VERSION 5.7 ;
BUSBITCHARS "[]" ;
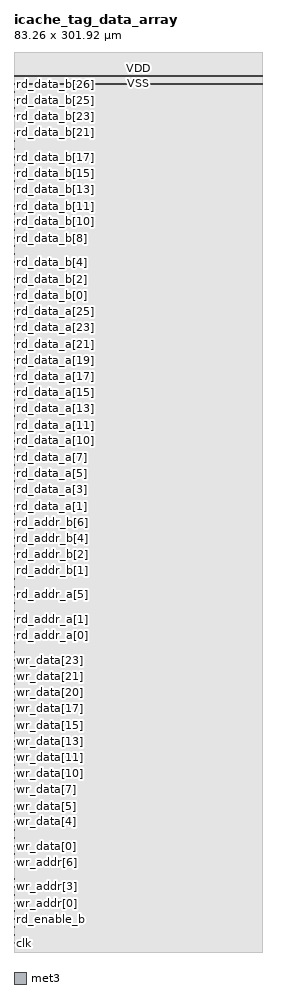
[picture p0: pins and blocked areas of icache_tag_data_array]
MACRO icache_tag_data_array
  FOREIGN icache_tag_data_array 0 0 ;
  SYMMETRY X Y R90 ;
  SIZE 83.260 BY 301.920 ;
  CLASS BLOCK ;
  PIN clk
    DIRECTION INPUT ;
    USE SIGNAL ;
    SHAPE ABUTMENT ;
    PORT
      LAYER met3 ;
      RECT 0.000 2.720 0.300 3.020 ;
    END
  END clk
  PIN wr_enable
    DIRECTION INPUT ;
    USE SIGNAL ;
    SHAPE ABUTMENT ;
    PORT
      LAYER met3 ;
      RECT 0.000 5.440 0.300 5.740 ;
    END
  END wr_enable
  PIN rd_enable_a
    DIRECTION INPUT ;
    USE SIGNAL ;
    SHAPE ABUTMENT ;
    PORT
      LAYER met3 ;
      RECT 0.000 8.160 0.300 8.460 ;
    END
  END rd_enable_a
  PIN rd_enable_b
    DIRECTION INPUT ;
    USE SIGNAL ;
    SHAPE ABUTMENT ;
    PORT
      LAYER met3 ;
      RECT 0.000 10.880 0.300 11.180 ;
    END
  END rd_enable_b
  PIN wr_addr[0]
    DIRECTION INPUT ;
    USE SIGNAL ;
    SHAPE ABUTMENT ;
    PORT
      LAYER met3 ;
      RECT 0.000 13.600 0.300 13.900 ;
    END
  END wr_addr[0]
  PIN wr_addr[1]
    DIRECTION INPUT ;
    USE SIGNAL ;
    SHAPE ABUTMENT ;
    PORT
      LAYER met3 ;
      RECT 0.000 16.320 0.300 16.620 ;
    END
  END wr_addr[1]
  PIN wr_addr[2]
    DIRECTION INPUT ;
    USE SIGNAL ;
    SHAPE ABUTMENT ;
    PORT
      LAYER met3 ;
      RECT 0.000 19.040 0.300 19.340 ;
    END
  END wr_addr[2]
  PIN wr_addr[3]
    DIRECTION INPUT ;
    USE SIGNAL ;
    SHAPE ABUTMENT ;
    PORT
      LAYER met3 ;
      RECT 0.000 21.760 0.300 22.060 ;
    END
  END wr_addr[3]
  PIN wr_addr[4]
    DIRECTION INPUT ;
    USE SIGNAL ;
    SHAPE ABUTMENT ;
    PORT
      LAYER met3 ;
      RECT 0.000 24.480 0.300 24.780 ;
    END
  END wr_addr[4]
  PIN wr_addr[5]
    DIRECTION INPUT ;
    USE SIGNAL ;
    SHAPE ABUTMENT ;
    PORT
      LAYER met3 ;
      RECT 0.000 27.200 0.300 27.500 ;
    END
  END wr_addr[5]
  PIN wr_addr[6]
    DIRECTION INPUT ;
    USE SIGNAL ;
    SHAPE ABUTMENT ;
    PORT
      LAYER met3 ;
      RECT 0.000 29.920 0.300 30.220 ;
    END
  END wr_addr[6]
  PIN wr_data[0]
    DIRECTION INPUT ;
    USE SIGNAL ;
    SHAPE ABUTMENT ;
    PORT
      LAYER met3 ;
      RECT 0.000 32.640 0.300 32.940 ;
    END
  END wr_data[0]
  PIN wr_data[1]
    DIRECTION INPUT ;
    USE SIGNAL ;
    SHAPE ABUTMENT ;
    PORT
      LAYER met3 ;
      RECT 0.000 35.360 0.300 35.660 ;
    END
  END wr_data[1]
  PIN wr_data[2]
    DIRECTION INPUT ;
    USE SIGNAL ;
    SHAPE ABUTMENT ;
    PORT
      LAYER met3 ;
      RECT 0.000 38.080 0.300 38.380 ;
    END
  END wr_data[2]
  PIN wr_data[3]
    DIRECTION INPUT ;
    USE SIGNAL ;
    SHAPE ABUTMENT ;
    PORT
      LAYER met3 ;
      RECT 0.000 40.800 0.300 41.100 ;
    END
  END wr_data[3]
  PIN wr_data[4]
    DIRECTION INPUT ;
    USE SIGNAL ;
    SHAPE ABUTMENT ;
    PORT
      LAYER met3 ;
      RECT 0.000 43.520 0.300 43.820 ;
    END
  END wr_data[4]
  PIN wr_data[5]
    DIRECTION INPUT ;
    USE SIGNAL ;
    SHAPE ABUTMENT ;
    PORT
      LAYER met3 ;
      RECT 0.000 46.240 0.300 46.540 ;
    END
  END wr_data[5]
  PIN wr_data[6]
    DIRECTION INPUT ;
    USE SIGNAL ;
    SHAPE ABUTMENT ;
    PORT
      LAYER met3 ;
      RECT 0.000 48.960 0.300 49.260 ;
    END
  END wr_data[6]
  PIN wr_data[7]
    DIRECTION INPUT ;
    USE SIGNAL ;
    SHAPE ABUTMENT ;
    PORT
      LAYER met3 ;
      RECT 0.000 51.680 0.300 51.980 ;
    END
  END wr_data[7]
  PIN wr_data[8]
    DIRECTION INPUT ;
    USE SIGNAL ;
    SHAPE ABUTMENT ;
    PORT
      LAYER met3 ;
      RECT 0.000 54.400 0.300 54.700 ;
    END
  END wr_data[8]
  PIN wr_data[9]
    DIRECTION INPUT ;
    USE SIGNAL ;
    SHAPE ABUTMENT ;
    PORT
      LAYER met3 ;
      RECT 0.000 57.120 0.300 57.420 ;
    END
  END wr_data[9]
  PIN wr_data[10]
    DIRECTION INPUT ;
    USE SIGNAL ;
    SHAPE ABUTMENT ;
    PORT
      LAYER met3 ;
      RECT 0.000 59.840 0.300 60.140 ;
    END
  END wr_data[10]
  PIN wr_data[11]
    DIRECTION INPUT ;
    USE SIGNAL ;
    SHAPE ABUTMENT ;
    PORT
      LAYER met3 ;
      RECT 0.000 62.560 0.300 62.860 ;
    END
  END wr_data[11]
  PIN wr_data[12]
    DIRECTION INPUT ;
    USE SIGNAL ;
    SHAPE ABUTMENT ;
    PORT
      LAYER met3 ;
      RECT 0.000 65.280 0.300 65.580 ;
    END
  END wr_data[12]
  PIN wr_data[13]
    DIRECTION INPUT ;
    USE SIGNAL ;
    SHAPE ABUTMENT ;
    PORT
      LAYER met3 ;
      RECT 0.000 68.000 0.300 68.300 ;
    END
  END wr_data[13]
  PIN wr_data[14]
    DIRECTION INPUT ;
    USE SIGNAL ;
    SHAPE ABUTMENT ;
    PORT
      LAYER met3 ;
      RECT 0.000 70.720 0.300 71.020 ;
    END
  END wr_data[14]
  PIN wr_data[15]
    DIRECTION INPUT ;
    USE SIGNAL ;
    SHAPE ABUTMENT ;
    PORT
      LAYER met3 ;
      RECT 0.000 73.440 0.300 73.740 ;
    END
  END wr_data[15]
  PIN wr_data[16]
    DIRECTION INPUT ;
    USE SIGNAL ;
    SHAPE ABUTMENT ;
    PORT
      LAYER met3 ;
      RECT 0.000 76.160 0.300 76.460 ;
    END
  END wr_data[16]
  PIN wr_data[17]
    DIRECTION INPUT ;
    USE SIGNAL ;
    SHAPE ABUTMENT ;
    PORT
      LAYER met3 ;
      RECT 0.000 78.880 0.300 79.180 ;
    END
  END wr_data[17]
  PIN wr_data[18]
    DIRECTION INPUT ;
    USE SIGNAL ;
    SHAPE ABUTMENT ;
    PORT
      LAYER met3 ;
      RECT 0.000 81.600 0.300 81.900 ;
    END
  END wr_data[18]
  PIN wr_data[19]
    DIRECTION INPUT ;
    USE SIGNAL ;
    SHAPE ABUTMENT ;
    PORT
      LAYER met3 ;
      RECT 0.000 84.320 0.300 84.620 ;
    END
  END wr_data[19]
  PIN wr_data[20]
    DIRECTION INPUT ;
    USE SIGNAL ;
    SHAPE ABUTMENT ;
    PORT
      LAYER met3 ;
      RECT 0.000 87.040 0.300 87.340 ;
    END
  END wr_data[20]
  PIN wr_data[21]
    DIRECTION INPUT ;
    USE SIGNAL ;
    SHAPE ABUTMENT ;
    PORT
      LAYER met3 ;
      RECT 0.000 89.760 0.300 90.060 ;
    END
  END wr_data[21]
  PIN wr_data[22]
    DIRECTION INPUT ;
    USE SIGNAL ;
    SHAPE ABUTMENT ;
    PORT
      LAYER met3 ;
      RECT 0.000 92.480 0.300 92.780 ;
    END
  END wr_data[22]
  PIN wr_data[23]
    DIRECTION INPUT ;
    USE SIGNAL ;
    SHAPE ABUTMENT ;
    PORT
      LAYER met3 ;
      RECT 0.000 95.200 0.300 95.500 ;
    END
  END wr_data[23]
  PIN wr_data[24]
    DIRECTION INPUT ;
    USE SIGNAL ;
    SHAPE ABUTMENT ;
    PORT
      LAYER met3 ;
      RECT 0.000 97.920 0.300 98.220 ;
    END
  END wr_data[24]
  PIN wr_data[25]
    DIRECTION INPUT ;
    USE SIGNAL ;
    SHAPE ABUTMENT ;
    PORT
      LAYER met3 ;
      RECT 0.000 100.640 0.300 100.940 ;
    END
  END wr_data[25]
  PIN wr_data[26]
    DIRECTION INPUT ;
    USE SIGNAL ;
    SHAPE ABUTMENT ;
    PORT
      LAYER met3 ;
      RECT 0.000 103.360 0.300 103.660 ;
    END
  END wr_data[26]
  PIN rd_addr_a[0]
    DIRECTION INPUT ;
    USE SIGNAL ;
    SHAPE ABUTMENT ;
    PORT
      LAYER met3 ;
      RECT 0.000 106.080 0.300 106.380 ;
    END
  END rd_addr_a[0]
  PIN rd_addr_a[1]
    DIRECTION INPUT ;
    USE SIGNAL ;
    SHAPE ABUTMENT ;
    PORT
      LAYER met3 ;
      RECT 0.000 108.800 0.300 109.100 ;
    END
  END rd_addr_a[1]
  PIN rd_addr_a[2]
    DIRECTION INPUT ;
    USE SIGNAL ;
    SHAPE ABUTMENT ;
    PORT
      LAYER met3 ;
      RECT 0.000 111.520 0.300 111.820 ;
    END
  END rd_addr_a[2]
  PIN rd_addr_a[3]
    DIRECTION INPUT ;
    USE SIGNAL ;
    SHAPE ABUTMENT ;
    PORT
      LAYER met3 ;
      RECT 0.000 114.240 0.300 114.540 ;
    END
  END rd_addr_a[3]
  PIN rd_addr_a[4]
    DIRECTION INPUT ;
    USE SIGNAL ;
    SHAPE ABUTMENT ;
    PORT
      LAYER met3 ;
      RECT 0.000 116.960 0.300 117.260 ;
    END
  END rd_addr_a[4]
  PIN rd_addr_a[5]
    DIRECTION INPUT ;
    USE SIGNAL ;
    SHAPE ABUTMENT ;
    PORT
      LAYER met3 ;
      RECT 0.000 119.680 0.300 119.980 ;
    END
  END rd_addr_a[5]
  PIN rd_addr_a[6]
    DIRECTION INPUT ;
    USE SIGNAL ;
    SHAPE ABUTMENT ;
    PORT
      LAYER met3 ;
      RECT 0.000 122.400 0.300 122.700 ;
    END
  END rd_addr_a[6]
  PIN rd_addr_b[0]
    DIRECTION INPUT ;
    USE SIGNAL ;
    SHAPE ABUTMENT ;
    PORT
      LAYER met3 ;
      RECT 0.000 125.120 0.300 125.420 ;
    END
  END rd_addr_b[0]
  PIN rd_addr_b[1]
    DIRECTION INPUT ;
    USE SIGNAL ;
    SHAPE ABUTMENT ;
    PORT
      LAYER met3 ;
      RECT 0.000 127.840 0.300 128.140 ;
    END
  END rd_addr_b[1]
  PIN rd_addr_b[2]
    DIRECTION INPUT ;
    USE SIGNAL ;
    SHAPE ABUTMENT ;
    PORT
      LAYER met3 ;
      RECT 0.000 130.560 0.300 130.860 ;
    END
  END rd_addr_b[2]
  PIN rd_addr_b[3]
    DIRECTION INPUT ;
    USE SIGNAL ;
    SHAPE ABUTMENT ;
    PORT
      LAYER met3 ;
      RECT 0.000 133.280 0.300 133.580 ;
    END
  END rd_addr_b[3]
  PIN rd_addr_b[4]
    DIRECTION INPUT ;
    USE SIGNAL ;
    SHAPE ABUTMENT ;
    PORT
      LAYER met3 ;
      RECT 0.000 136.000 0.300 136.300 ;
    END
  END rd_addr_b[4]
  PIN rd_addr_b[5]
    DIRECTION INPUT ;
    USE SIGNAL ;
    SHAPE ABUTMENT ;
    PORT
      LAYER met3 ;
      RECT 0.000 138.720 0.300 139.020 ;
    END
  END rd_addr_b[5]
  PIN rd_addr_b[6]
    DIRECTION INPUT ;
    USE SIGNAL ;
    SHAPE ABUTMENT ;
    PORT
      LAYER met3 ;
      RECT 0.000 141.440 0.300 141.740 ;
    END
  END rd_addr_b[6]
  PIN rd_data_a[0]
    DIRECTION OUTPUT ;
    USE SIGNAL ;
    SHAPE ABUTMENT ;
    PORT
      LAYER met3 ;
      RECT 0.000 144.160 0.300 144.460 ;
    END
  END rd_data_a[0]
  PIN rd_data_a[1]
    DIRECTION OUTPUT ;
    USE SIGNAL ;
    SHAPE ABUTMENT ;
    PORT
      LAYER met3 ;
      RECT 0.000 146.880 0.300 147.180 ;
    END
  END rd_data_a[1]
  PIN rd_data_a[2]
    DIRECTION OUTPUT ;
    USE SIGNAL ;
    SHAPE ABUTMENT ;
    PORT
      LAYER met3 ;
      RECT 0.000 149.600 0.300 149.900 ;
    END
  END rd_data_a[2]
  PIN rd_data_a[3]
    DIRECTION OUTPUT ;
    USE SIGNAL ;
    SHAPE ABUTMENT ;
    PORT
      LAYER met3 ;
      RECT 0.000 152.320 0.300 152.620 ;
    END
  END rd_data_a[3]
  PIN rd_data_a[4]
    DIRECTION OUTPUT ;
    USE SIGNAL ;
    SHAPE ABUTMENT ;
    PORT
      LAYER met3 ;
      RECT 0.000 155.040 0.300 155.340 ;
    END
  END rd_data_a[4]
  PIN rd_data_a[5]
    DIRECTION OUTPUT ;
    USE SIGNAL ;
    SHAPE ABUTMENT ;
    PORT
      LAYER met3 ;
      RECT 0.000 157.760 0.300 158.060 ;
    END
  END rd_data_a[5]
  PIN rd_data_a[6]
    DIRECTION OUTPUT ;
    USE SIGNAL ;
    SHAPE ABUTMENT ;
    PORT
      LAYER met3 ;
      RECT 0.000 160.480 0.300 160.780 ;
    END
  END rd_data_a[6]
  PIN rd_data_a[7]
    DIRECTION OUTPUT ;
    USE SIGNAL ;
    SHAPE ABUTMENT ;
    PORT
      LAYER met3 ;
      RECT 0.000 163.200 0.300 163.500 ;
    END
  END rd_data_a[7]
  PIN rd_data_a[8]
    DIRECTION OUTPUT ;
    USE SIGNAL ;
    SHAPE ABUTMENT ;
    PORT
      LAYER met3 ;
      RECT 0.000 165.920 0.300 166.220 ;
    END
  END rd_data_a[8]
  PIN rd_data_a[9]
    DIRECTION OUTPUT ;
    USE SIGNAL ;
    SHAPE ABUTMENT ;
    PORT
      LAYER met3 ;
      RECT 0.000 168.640 0.300 168.940 ;
    END
  END rd_data_a[9]
  PIN rd_data_a[10]
    DIRECTION OUTPUT ;
    USE SIGNAL ;
    SHAPE ABUTMENT ;
    PORT
      LAYER met3 ;
      RECT 0.000 171.360 0.300 171.660 ;
    END
  END rd_data_a[10]
  PIN rd_data_a[11]
    DIRECTION OUTPUT ;
    USE SIGNAL ;
    SHAPE ABUTMENT ;
    PORT
      LAYER met3 ;
      RECT 0.000 174.080 0.300 174.380 ;
    END
  END rd_data_a[11]
  PIN rd_data_a[12]
    DIRECTION OUTPUT ;
    USE SIGNAL ;
    SHAPE ABUTMENT ;
    PORT
      LAYER met3 ;
      RECT 0.000 176.800 0.300 177.100 ;
    END
  END rd_data_a[12]
  PIN rd_data_a[13]
    DIRECTION OUTPUT ;
    USE SIGNAL ;
    SHAPE ABUTMENT ;
    PORT
      LAYER met3 ;
      RECT 0.000 179.520 0.300 179.820 ;
    END
  END rd_data_a[13]
  PIN rd_data_a[14]
    DIRECTION OUTPUT ;
    USE SIGNAL ;
    SHAPE ABUTMENT ;
    PORT
      LAYER met3 ;
      RECT 0.000 182.240 0.300 182.540 ;
    END
  END rd_data_a[14]
  PIN rd_data_a[15]
    DIRECTION OUTPUT ;
    USE SIGNAL ;
    SHAPE ABUTMENT ;
    PORT
      LAYER met3 ;
      RECT 0.000 184.960 0.300 185.260 ;
    END
  END rd_data_a[15]
  PIN rd_data_a[16]
    DIRECTION OUTPUT ;
    USE SIGNAL ;
    SHAPE ABUTMENT ;
    PORT
      LAYER met3 ;
      RECT 0.000 187.680 0.300 187.980 ;
    END
  END rd_data_a[16]
  PIN rd_data_a[17]
    DIRECTION OUTPUT ;
    USE SIGNAL ;
    SHAPE ABUTMENT ;
    PORT
      LAYER met3 ;
      RECT 0.000 190.400 0.300 190.700 ;
    END
  END rd_data_a[17]
  PIN rd_data_a[18]
    DIRECTION OUTPUT ;
    USE SIGNAL ;
    SHAPE ABUTMENT ;
    PORT
      LAYER met3 ;
      RECT 0.000 193.120 0.300 193.420 ;
    END
  END rd_data_a[18]
  PIN rd_data_a[19]
    DIRECTION OUTPUT ;
    USE SIGNAL ;
    SHAPE ABUTMENT ;
    PORT
      LAYER met3 ;
      RECT 0.000 195.840 0.300 196.140 ;
    END
  END rd_data_a[19]
  PIN rd_data_a[20]
    DIRECTION OUTPUT ;
    USE SIGNAL ;
    SHAPE ABUTMENT ;
    PORT
      LAYER met3 ;
      RECT 0.000 198.560 0.300 198.860 ;
    END
  END rd_data_a[20]
  PIN rd_data_a[21]
    DIRECTION OUTPUT ;
    USE SIGNAL ;
    SHAPE ABUTMENT ;
    PORT
      LAYER met3 ;
      RECT 0.000 201.280 0.300 201.580 ;
    END
  END rd_data_a[21]
  PIN rd_data_a[22]
    DIRECTION OUTPUT ;
    USE SIGNAL ;
    SHAPE ABUTMENT ;
    PORT
      LAYER met3 ;
      RECT 0.000 204.000 0.300 204.300 ;
    END
  END rd_data_a[22]
  PIN rd_data_a[23]
    DIRECTION OUTPUT ;
    USE SIGNAL ;
    SHAPE ABUTMENT ;
    PORT
      LAYER met3 ;
      RECT 0.000 206.720 0.300 207.020 ;
    END
  END rd_data_a[23]
  PIN rd_data_a[24]
    DIRECTION OUTPUT ;
    USE SIGNAL ;
    SHAPE ABUTMENT ;
    PORT
      LAYER met3 ;
      RECT 0.000 209.440 0.300 209.740 ;
    END
  END rd_data_a[24]
  PIN rd_data_a[25]
    DIRECTION OUTPUT ;
    USE SIGNAL ;
    SHAPE ABUTMENT ;
    PORT
      LAYER met3 ;
      RECT 0.000 212.160 0.300 212.460 ;
    END
  END rd_data_a[25]
  PIN rd_data_a[26]
    DIRECTION OUTPUT ;
    USE SIGNAL ;
    SHAPE ABUTMENT ;
    PORT
      LAYER met3 ;
      RECT 0.000 214.880 0.300 215.180 ;
    END
  END rd_data_a[26]
  PIN rd_data_b[0]
    DIRECTION OUTPUT ;
    USE SIGNAL ;
    SHAPE ABUTMENT ;
    PORT
      LAYER met3 ;
      RECT 0.000 217.600 0.300 217.900 ;
    END
  END rd_data_b[0]
  PIN rd_data_b[1]
    DIRECTION OUTPUT ;
    USE SIGNAL ;
    SHAPE ABUTMENT ;
    PORT
      LAYER met3 ;
      RECT 0.000 220.320 0.300 220.620 ;
    END
  END rd_data_b[1]
  PIN rd_data_b[2]
    DIRECTION OUTPUT ;
    USE SIGNAL ;
    SHAPE ABUTMENT ;
    PORT
      LAYER met3 ;
      RECT 0.000 223.040 0.300 223.340 ;
    END
  END rd_data_b[2]
  PIN rd_data_b[3]
    DIRECTION OUTPUT ;
    USE SIGNAL ;
    SHAPE ABUTMENT ;
    PORT
      LAYER met3 ;
      RECT 0.000 225.760 0.300 226.060 ;
    END
  END rd_data_b[3]
  PIN rd_data_b[4]
    DIRECTION OUTPUT ;
    USE SIGNAL ;
    SHAPE ABUTMENT ;
    PORT
      LAYER met3 ;
      RECT 0.000 228.480 0.300 228.780 ;
    END
  END rd_data_b[4]
  PIN rd_data_b[5]
    DIRECTION OUTPUT ;
    USE SIGNAL ;
    SHAPE ABUTMENT ;
    PORT
      LAYER met3 ;
      RECT 0.000 231.200 0.300 231.500 ;
    END
  END rd_data_b[5]
  PIN rd_data_b[6]
    DIRECTION OUTPUT ;
    USE SIGNAL ;
    SHAPE ABUTMENT ;
    PORT
      LAYER met3 ;
      RECT 0.000 233.920 0.300 234.220 ;
    END
  END rd_data_b[6]
  PIN rd_data_b[7]
    DIRECTION OUTPUT ;
    USE SIGNAL ;
    SHAPE ABUTMENT ;
    PORT
      LAYER met3 ;
      RECT 0.000 236.640 0.300 236.940 ;
    END
  END rd_data_b[7]
  PIN rd_data_b[8]
    DIRECTION OUTPUT ;
    USE SIGNAL ;
    SHAPE ABUTMENT ;
    PORT
      LAYER met3 ;
      RECT 0.000 239.360 0.300 239.660 ;
    END
  END rd_data_b[8]
  PIN rd_data_b[9]
    DIRECTION OUTPUT ;
    USE SIGNAL ;
    SHAPE ABUTMENT ;
    PORT
      LAYER met3 ;
      RECT 0.000 242.080 0.300 242.380 ;
    END
  END rd_data_b[9]
  PIN rd_data_b[10]
    DIRECTION OUTPUT ;
    USE SIGNAL ;
    SHAPE ABUTMENT ;
    PORT
      LAYER met3 ;
      RECT 0.000 244.800 0.300 245.100 ;
    END
  END rd_data_b[10]
  PIN rd_data_b[11]
    DIRECTION OUTPUT ;
    USE SIGNAL ;
    SHAPE ABUTMENT ;
    PORT
      LAYER met3 ;
      RECT 0.000 247.520 0.300 247.820 ;
    END
  END rd_data_b[11]
  PIN rd_data_b[12]
    DIRECTION OUTPUT ;
    USE SIGNAL ;
    SHAPE ABUTMENT ;
    PORT
      LAYER met3 ;
      RECT 0.000 250.240 0.300 250.540 ;
    END
  END rd_data_b[12]
  PIN rd_data_b[13]
    DIRECTION OUTPUT ;
    USE SIGNAL ;
    SHAPE ABUTMENT ;
    PORT
      LAYER met3 ;
      RECT 0.000 252.960 0.300 253.260 ;
    END
  END rd_data_b[13]
  PIN rd_data_b[14]
    DIRECTION OUTPUT ;
    USE SIGNAL ;
    SHAPE ABUTMENT ;
    PORT
      LAYER met3 ;
      RECT 0.000 255.680 0.300 255.980 ;
    END
  END rd_data_b[14]
  PIN rd_data_b[15]
    DIRECTION OUTPUT ;
    USE SIGNAL ;
    SHAPE ABUTMENT ;
    PORT
      LAYER met3 ;
      RECT 0.000 258.400 0.300 258.700 ;
    END
  END rd_data_b[15]
  PIN rd_data_b[16]
    DIRECTION OUTPUT ;
    USE SIGNAL ;
    SHAPE ABUTMENT ;
    PORT
      LAYER met3 ;
      RECT 0.000 261.120 0.300 261.420 ;
    END
  END rd_data_b[16]
  PIN rd_data_b[17]
    DIRECTION OUTPUT ;
    USE SIGNAL ;
    SHAPE ABUTMENT ;
    PORT
      LAYER met3 ;
      RECT 0.000 263.840 0.300 264.140 ;
    END
  END rd_data_b[17]
  PIN rd_data_b[18]
    DIRECTION OUTPUT ;
    USE SIGNAL ;
    SHAPE ABUTMENT ;
    PORT
      LAYER met3 ;
      RECT 0.000 266.560 0.300 266.860 ;
    END
  END rd_data_b[18]
  PIN rd_data_b[19]
    DIRECTION OUTPUT ;
    USE SIGNAL ;
    SHAPE ABUTMENT ;
    PORT
      LAYER met3 ;
      RECT 0.000 269.280 0.300 269.580 ;
    END
  END rd_data_b[19]
  PIN rd_data_b[20]
    DIRECTION OUTPUT ;
    USE SIGNAL ;
    SHAPE ABUTMENT ;
    PORT
      LAYER met3 ;
      RECT 0.000 272.000 0.300 272.300 ;
    END
  END rd_data_b[20]
  PIN rd_data_b[21]
    DIRECTION OUTPUT ;
    USE SIGNAL ;
    SHAPE ABUTMENT ;
    PORT
      LAYER met3 ;
      RECT 0.000 274.720 0.300 275.020 ;
    END
  END rd_data_b[21]
  PIN rd_data_b[22]
    DIRECTION OUTPUT ;
    USE SIGNAL ;
    SHAPE ABUTMENT ;
    PORT
      LAYER met3 ;
      RECT 0.000 277.440 0.300 277.740 ;
    END
  END rd_data_b[22]
  PIN rd_data_b[23]
    DIRECTION OUTPUT ;
    USE SIGNAL ;
    SHAPE ABUTMENT ;
    PORT
      LAYER met3 ;
      RECT 0.000 280.160 0.300 280.460 ;
    END
  END rd_data_b[23]
  PIN rd_data_b[24]
    DIRECTION OUTPUT ;
    USE SIGNAL ;
    SHAPE ABUTMENT ;
    PORT
      LAYER met3 ;
      RECT 0.000 282.880 0.300 283.180 ;
    END
  END rd_data_b[24]
  PIN rd_data_b[25]
    DIRECTION OUTPUT ;
    USE SIGNAL ;
    SHAPE ABUTMENT ;
    PORT
      LAYER met3 ;
      RECT 0.000 285.600 0.300 285.900 ;
    END
  END rd_data_b[25]
  PIN rd_data_b[26]
    DIRECTION OUTPUT ;
    USE SIGNAL ;
    SHAPE ABUTMENT ;
    PORT
      LAYER met3 ;
      RECT 0.000 288.320 0.300 288.620 ;
    END
  END rd_data_b[26]
  PIN VSS
    DIRECTION INOUT ;
    USE GROUND ;
    SHAPE ABUTMENT ;
    PORT
      LAYER met3 ;
      RECT 0.000 291.040 83.260 291.340 ;
    END
  END VSS
  PIN VDD
    DIRECTION INOUT ;
    USE POWER ;
    SHAPE ABUTMENT ;
    PORT
      LAYER met3 ;
      RECT 0.000 293.760 83.260 294.060 ;
    END
  END VDD
  OBS
    LAYER li1 ;
      RECT 0.000 0.000 83.260 301.920 ;
    LAYER met1 ;
      RECT 0.000 0.000 83.260 301.920 ;
    LAYER met2 ;
      RECT 0.000 0.000 83.260 301.920 ;
    LAYER met3 ;
      RECT 0.000 0.000 83.260 301.920 ;
    LAYER met4 ;
      RECT 0.000 0.000 83.260 301.920 ;
  END
END icache_tag_data_array
END LIBRARY
